VERSION 5.8 ;
BUSBITCHARS "[]" ;
DIVIDERCHAR "/" ;
UNITS
    DATABASE MICRONS 1000 ;
END UNITS

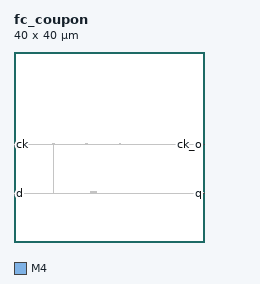
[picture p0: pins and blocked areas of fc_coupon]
MACRO fc_coupon
  FOREIGN fc_coupon 0 0 ;
  CLASS BLOCK ;
  SIZE 40 BY 40 ;
  PIN VDD
    USE POWER ;
    DIRECTION INOUT ;
  END VDD
  PIN VSS
    USE GROUND ;
    DIRECTION INOUT ;
  END VSS
  PIN ck
    DIRECTION INPUT ;
    USE SIGNAL ;
    PORT
      LAYER M4 ;
        RECT  0 20.496 0.084 20.52 ;
    END
  END ck
  PIN ck_o
    DIRECTION OUTPUT ;
    USE SIGNAL ;
    PORT
      LAYER M4 ;
        RECT  39.916 20.496 40 20.52 ;
    END
  END ck_o
  PIN d
    DIRECTION INPUT ;
    USE SIGNAL ;
    PORT
      LAYER M4 ;
        RECT  0 10.272 0.084 10.296 ;
    END
  END d
  PIN q
    DIRECTION OUTPUT ;
    USE SIGNAL ;
    PORT
      LAYER M4 ;
        RECT  39.916 10.272 40 10.296 ;
    END
  END q
  OBS
    LAYER RVTN ;
     RECT  16.2 10.26 17.28 10.395 ;
     RECT  8.1 20.52 8.478 20.655 ;
     RECT  15.12 20.52 15.39 20.655 ;
     RECT  22.14 20.52 22.41 20.655 ;
    LAYER RVTP ;
     RECT  16.2 10.395 17.28 10.53 ;
     RECT  8.1 20.655 8.478 20.79 ;
     RECT  15.12 20.655 15.39 20.79 ;
     RECT  22.14 20.655 22.41 20.79 ;
    LAYER M1 ;
     RECT  16.2 10.251 17.28 10.539 ;
     RECT  8.1 20.511 8.478 20.799 ;
     RECT  15.12 20.511 15.39 20.799 ;
     RECT  22.14 20.511 22.41 20.799 ;
    LAYER M2 ;
     RECT  8.131 20.592 8.159 20.61 ;
     RECT  7.411 10.251 8.239 10.269 ;
     RECT  8.239 10.251 16.219 10.314 ;
     RECT  16.219 10.251 16.375 10.422 ;
     RECT  16.375 10.251 16.475 10.458 ;
     RECT  16.475 10.404 16.727 10.458 ;
     RECT  16.727 10.404 17.213 10.422 ;
     RECT  8.419 20.556 22.171 20.574 ;
     RECT  22.171 20.556 22.199 20.718 ;
     RECT  22.199 20.556 31.343 20.574 ;
     RECT  17.239 10.296 39.911 10.314 ;
    LAYER M3 ;
     RECT  7.416 10.246 7.434 10.301 ;
     RECT  16.452 10.246 16.47 10.319 ;
     RECT  39.888 10.267 39.906 10.319 ;
     RECT  8.244 10.291 8.262 20.491 ;
     RECT  8.136 20.491 8.262 20.525 ;
     RECT  31.32 20.491 31.338 20.579 ;
     RECT  8.136 20.525 8.154 20.615 ;
     RECT  22.176 20.551 22.194 20.723 ;
    LAYER M4 ;
     RECT  0.06 10.272 7.445 10.296 ;
     RECT  0.06 20.496 8.273 20.52 ;
     RECT  39.877 10.272 39.948 10.296 ;
     RECT  31.309 20.496 39.948 20.52 ;
  END
END fc_coupon
END LIBRARY
